VERSION 5.7 ;
  NOWIREEXTENSIONATPIN ON ;
  DIVIDERCHAR "/" ;
  BUSBITCHARS "[]" ;
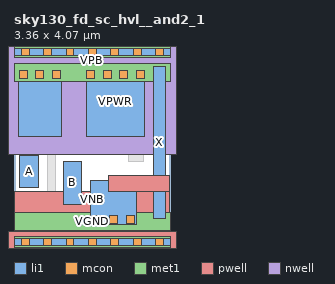
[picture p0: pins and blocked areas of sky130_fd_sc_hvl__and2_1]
MACRO sky130_fd_sc_hvl__and2_1
  CLASS BLOCK ;
  FOREIGN sky130_fd_sc_hvl__and2_1 ;
  ORIGIN 0.000 0.000 ;
  SIZE 3.360 BY 4.070 ;
  PIN A
    ANTENNAGATEAREA 0.420000 ;
    PORT
      LAYER li1 ;
        RECT 0.125 1.175 0.535 1.845 ;
    END
  END A
  PIN B
    ANTENNAGATEAREA 0.420000 ;
    PORT
      LAYER li1 ;
        RECT 1.065 0.810 1.455 1.725 ;
    END
  END B
  PIN VGND
    USE GROUND ;
    PORT
      LAYER li1 ;
        RECT 1.635 0.365 2.625 1.325 ;
      LAYER mcon ;
        RECT 1.685 0.395 1.855 0.565 ;
        RECT 2.045 0.395 2.215 0.565 ;
        RECT 2.405 0.395 2.575 0.565 ;
      LAYER met1 ;
        RECT 0.000 0.255 3.360 0.625 ;
    END
  END VGND
  PIN VNB
    ANTENNADIFFAREA 0.571200 ;
    PORT
      LAYER pwell ;
        RECT 2.030 1.085 3.340 1.415 ;
        RECT 0.020 0.215 3.340 1.085 ;
        RECT -0.130 -0.215 3.490 0.215 ;
      LAYER li1 ;
        RECT 0.000 -0.085 3.360 0.085 ;
      LAYER mcon ;
        RECT 0.155 -0.085 0.325 0.085 ;
        RECT 0.635 -0.085 0.805 0.085 ;
        RECT 1.115 -0.085 1.285 0.085 ;
        RECT 1.595 -0.085 1.765 0.085 ;
        RECT 2.075 -0.085 2.245 0.085 ;
        RECT 2.555 -0.085 2.725 0.085 ;
        RECT 3.035 -0.085 3.205 0.085 ;
      LAYER met1 ;
        RECT 0.000 -0.115 3.360 0.115 ;
    END
  END VNB
  PIN VPB
    ANTENNADIFFAREA 0.571200 ;
    PORT
      LAYER nwell ;
        RECT -0.330 1.885 3.690 4.485 ;
      LAYER li1 ;
        RECT 0.000 3.985 3.360 4.155 ;
      LAYER mcon ;
        RECT 0.155 3.985 0.325 4.155 ;
        RECT 0.635 3.985 0.805 4.155 ;
        RECT 1.115 3.985 1.285 4.155 ;
        RECT 1.595 3.985 1.765 4.155 ;
        RECT 2.075 3.985 2.245 4.155 ;
        RECT 2.555 3.985 2.725 4.155 ;
        RECT 3.035 3.985 3.205 4.155 ;
      LAYER met1 ;
        RECT 0.000 3.955 3.360 4.185 ;
    END
  END VPB
  PIN VPWR
    USE POWER ;
    PORT
      LAYER li1 ;
        RECT 0.090 2.255 1.020 3.705 ;
        RECT 1.550 2.255 2.800 3.755 ;
      LAYER mcon ;
        RECT 0.110 3.505 0.280 3.675 ;
        RECT 0.470 3.505 0.640 3.675 ;
        RECT 0.830 3.505 1.000 3.675 ;
        RECT 1.550 3.505 1.720 3.675 ;
        RECT 1.910 3.505 2.080 3.675 ;
        RECT 2.270 3.505 2.440 3.675 ;
        RECT 2.630 3.505 2.800 3.675 ;
      LAYER met1 ;
        RECT 0.000 3.445 3.360 3.815 ;
    END
  END VPWR
  PIN X
    ANTENNADIFFAREA 0.626250 ;
    PORT
      LAYER li1 ;
        RECT 2.980 0.495 3.255 3.755 ;
    END
  END X
  OBS
      LAYER li1 ;
        RECT 1.200 2.075 1.370 2.675 ;
        RECT 0.715 1.905 2.775 2.075 ;
        RECT 0.715 0.995 0.885 1.905 ;
        RECT 2.445 1.725 2.775 1.905 ;
        RECT 0.130 0.825 0.885 0.995 ;
        RECT 0.130 0.495 0.380 0.825 ;
  END
END sky130_fd_sc_hvl__and2_1
END LIBRARY

